(* Logix 5000 AddOnInstructionDefinition export MCFG_Yaskawa; software revision 17.00; part 2 of 2 *)
(* tags used below, declared in another part *)
   Axis_OUT : AB:ETHERNET_MODULE_DINT_256Bytes:O:0;
   Axis : Yaskawa_EIP_Servo;
   FeedRateOverride : INT;   // Speed Override: 1% - 200% (100% = programmed speed)
(* MCFG_Yaskawa, continued *)

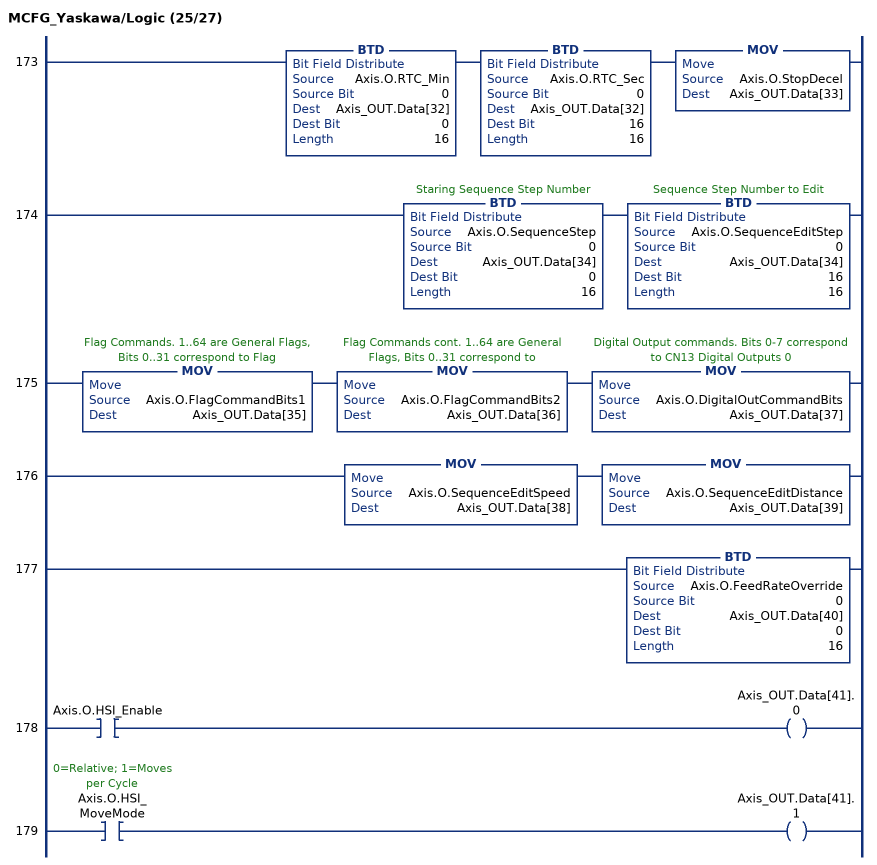
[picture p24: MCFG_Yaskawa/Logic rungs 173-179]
   173: BTD(Axis.O.RTC_Min,0,Axis_OUT.Data[32],0,16)BTD(Axis.O.RTC_Sec,0,Axis_OUT.Data[32],16,16)MOV(Axis.O.StopDecel,Axis_OUT.Data[33]);
   174: BTD(Axis.O.SequenceStep,0,Axis_OUT.Data[34],0,16)BTD(Axis.O.SequenceEditStep,0,Axis_OUT.Data[34],16,16);
   175: MOV(Axis.O.FlagCommandBits1,Axis_OUT.Data[35])MOV(Axis.O.FlagCommandBits2,Axis_OUT.Data[36])MOV(Axis.O.DigitalOutCommandBits,Axis_OUT.Data[37]);
   176: MOV(Axis.O.SequenceEditSpeed,Axis_OUT.Data[38])MOV(Axis.O.SequenceEditDistance,Axis_OUT.Data[39]);
   177: BTD(Axis.O.FeedRateOverride,0,Axis_OUT.Data[40],0,16);
   178: XIC(Axis.O.HSI_Enable)OTE(Axis_OUT.Data[41].0);
   179: XIC(Axis.O.HSI_MoveMode)OTE(Axis_OUT.Data[41].1);
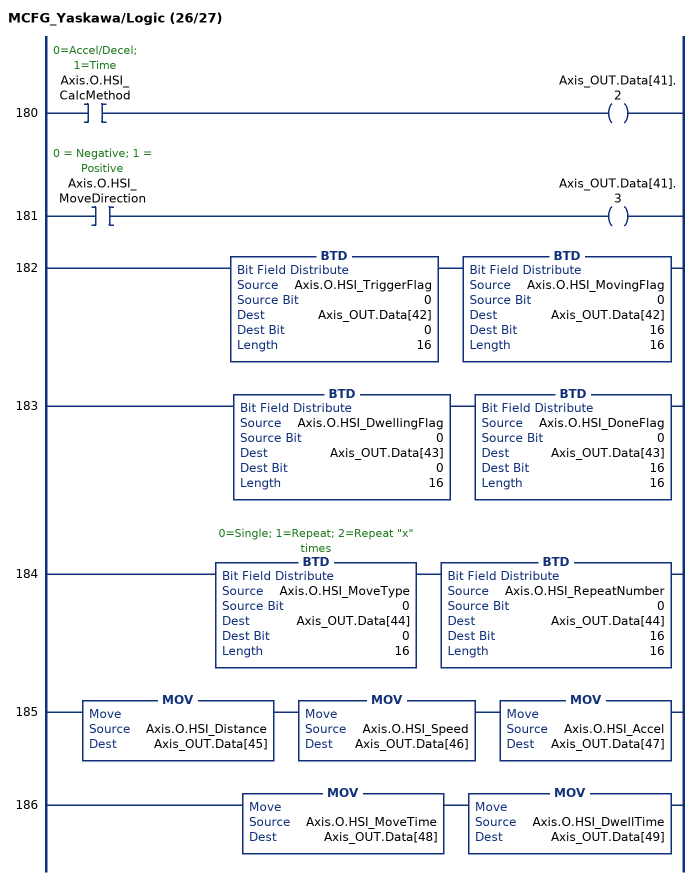
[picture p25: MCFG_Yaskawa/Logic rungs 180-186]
   180: XIC(Axis.O.HSI_CalcMethod)OTE(Axis_OUT.Data[41].2);
   181: XIC(Axis.O.HSI_MoveDirection)OTE(Axis_OUT.Data[41].3);
   182: BTD(Axis.O.HSI_TriggerFlag,0,Axis_OUT.Data[42],0,16)BTD(Axis.O.HSI_MovingFlag,0,Axis_OUT.Data[42],16,16);
   183: BTD(Axis.O.HSI_DwellingFlag,0,Axis_OUT.Data[43],0,16)BTD(Axis.O.HSI_DoneFlag,0,Axis_OUT.Data[43],16,16);
   184: BTD(Axis.O.HSI_MoveType,0,Axis_OUT.Data[44],0,16)BTD(Axis.O.HSI_RepeatNumber,0,Axis_OUT.Data[44],16,16);
   185: MOV(Axis.O.HSI_Distance,Axis_OUT.Data[45])MOV(Axis.O.HSI_Speed,Axis_OUT.Data[46])MOV(Axis.O.HSI_Accel,Axis_OUT.Data[47]);
   186: MOV(Axis.O.HSI_MoveTime,Axis_OUT.Data[48])MOV(Axis.O.HSI_DwellTime,Axis_OUT.Data[49]);
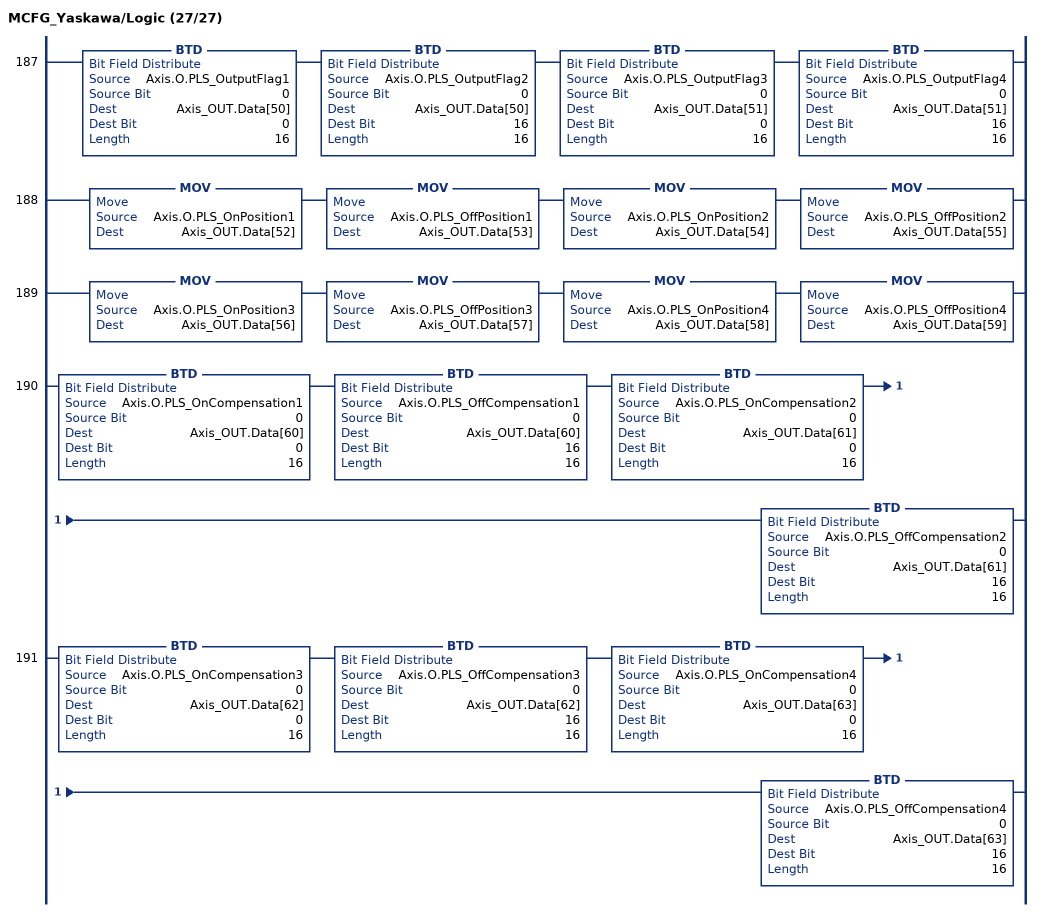
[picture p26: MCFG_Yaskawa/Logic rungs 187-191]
   187: BTD(Axis.O.PLS_OutputFlag1,0,Axis_OUT.Data[50],0,16)BTD(Axis.O.PLS_OutputFlag2,0,Axis_OUT.Data[50],16,16)BTD(Axis.O.PLS_OutputFlag3,0,Axis_OUT.Data[51],0,16)BTD(Axis.O.PLS_OutputFlag4,0,Axis_OUT.Data[51],16,16);
   188: MOV(Axis.O.PLS_OnPosition1,Axis_OUT.Data[52])MOV(Axis.O.PLS_OffPosition1,Axis_OUT.Data[53])MOV(Axis.O.PLS_OnPosition2,Axis_OUT.Data[54])MOV(Axis.O.PLS_OffPosition2,Axis_OUT.Data[55]);
   189: MOV(Axis.O.PLS_OnPosition3,Axis_OUT.Data[56])MOV(Axis.O.PLS_OffPosition3,Axis_OUT.Data[57])MOV(Axis.O.PLS_OnPosition4,Axis_OUT.Data[58])MOV(Axis.O.PLS_OffPosition4,Axis_OUT.Data[59]);
   190: BTD(Axis.O.PLS_OnCompensation1,0,Axis_OUT.Data[60],0,16)BTD(Axis.O.PLS_OffCompensation1,0,Axis_OUT.Data[60],16,16)BTD(Axis.O.PLS_OnCompensation2,0,Axis_OUT.Data[61],0,16)BTD(Axis.O.PLS_OffCompensation2,0,Axis_OUT.Data[61],16,16);
   191: BTD(Axis.O.PLS_OnCompensation3,0,Axis_OUT.Data[62],0,16)BTD(Axis.O.PLS_OffCompensation3,0,Axis_OUT.Data[62],16,16)BTD(Axis.O.PLS_OnCompensation4,0,Axis_OUT.Data[63],0,16)BTD(Axis.O.PLS_OffCompensation4,0,Axis_OUT.Data[63],16,16);
END_ROUTINE

ROUTINE Prescan   (* ladder *)
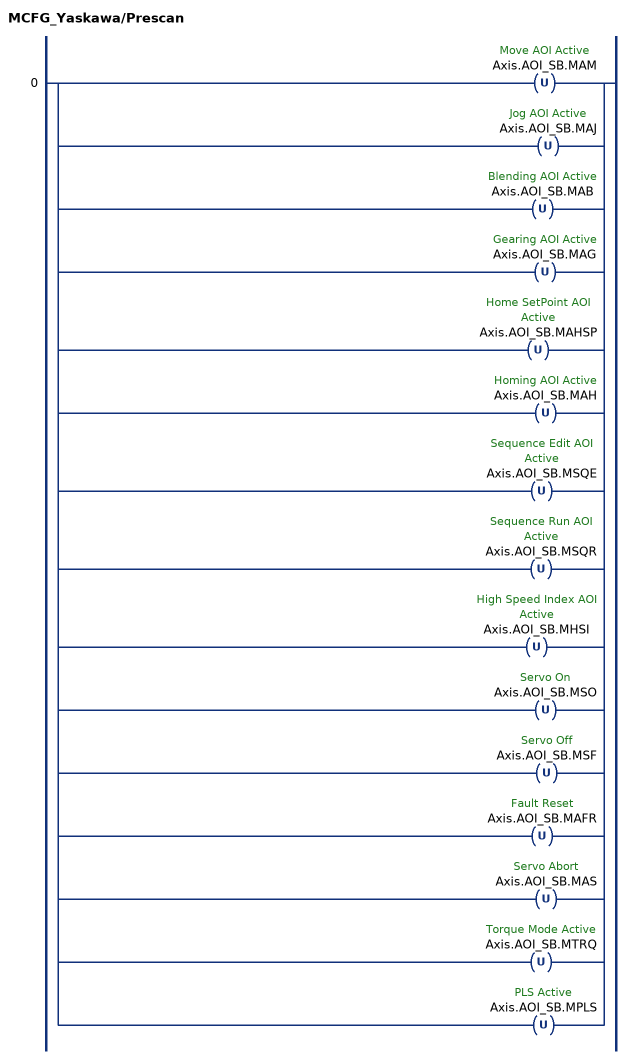
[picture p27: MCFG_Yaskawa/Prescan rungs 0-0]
   0: [OTU(Axis.AOI_SB.MAM) ,OTU(Axis.AOI_SB.MAJ) ,OTU(Axis.AOI_SB.MAB) ,OTU(Axis.AOI_SB.MAG) ,OTU(Axis.AOI_SB.MAHSP) ,OTU(Axis.AOI_SB.MAH) ,OTU(Axis.AOI_SB.MSQE) ,OTU(Axis.AOI_SB.MSQR) ,OTU(Axis.AOI_SB.MHSI) ,OTU(Axis.AOI_SB.MSO) ,OTU(Axis.AOI_SB.MSF) ,OTU(Axis.AOI_SB.MAFR) ,OTU(Axis.AOI_SB.MAS) ,OTU(Axis.AOI_SB.MTRQ) ,OTU(Axis.AOI_SB.MPLS) ];
END_ROUTINE
END_ADD_ON_INSTRUCTION
